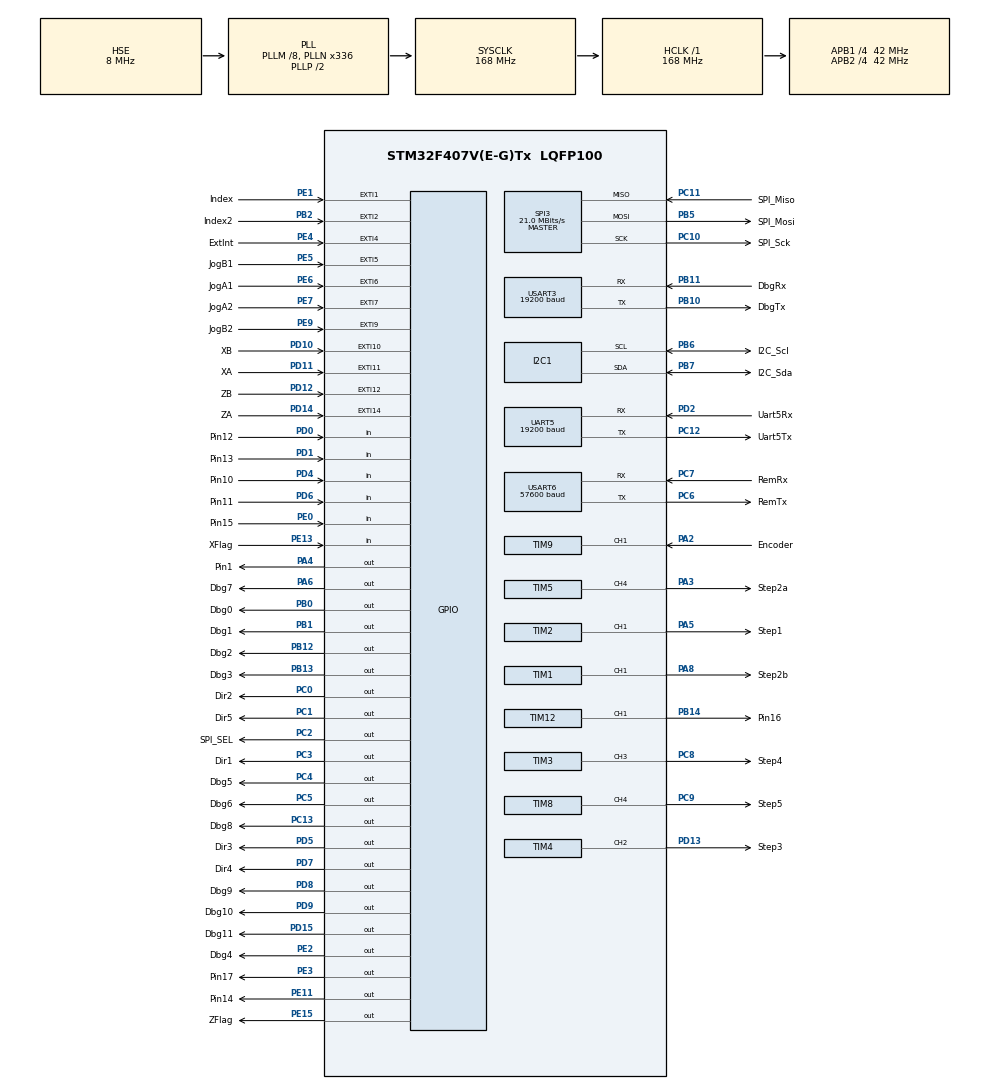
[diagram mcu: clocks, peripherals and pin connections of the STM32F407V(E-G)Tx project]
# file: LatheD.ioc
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Mcu.Family=STM32F4
Mcu.Name=STM32F407V(E-G)Tx
Mcu.Package=LQFP100
NVIC.EXTI15_10_IRQn=true\:5\:0\:true\:false\:false\:true\:false
NVIC.EXTI2_IRQn=true\:5\:0\:true\:false\:false\:true\:false
NVIC.EXTI4_IRQn=true\:5\:0\:true\:false\:false\:true\:false
NVIC.EXTI9_5_IRQn=true\:5\:0\:true\:false\:false\:true\:false
NVIC.PriorityGroup=NVIC_PRIORITYGROUP_4
NVIC.TIM1_BRK_TIM9_IRQn=true\:6\:0\:true\:false\:false\:true\:false
NVIC.TIM1_TRG_COM_TIM11_IRQn=true\:6\:0\:true\:false\:false\:true\:false
NVIC.TIM1_UP_TIM10_IRQn=true\:4\:0\:true\:false\:false\:true\:false
NVIC.TIM2_IRQn=true\:3\:0\:true\:false\:false\:true\:false
NVIC.TIM3_IRQn=true\:2\:0\:true\:false\:false\:true\:false
NVIC.TIM4_IRQn=true\:4\:0\:true\:false\:false\:true\:false
NVIC.TIM5_IRQn=true\:2\:0\:true\:false\:false\:true\:false
NVIC.TIM7_IRQn=true\:5\:0\:true\:false\:false\:true\:false
NVIC.TIM8_BRK_TIM12_IRQn=true\:5\:0\:true\:false\:false\:true\:false
NVIC.TIM8_TRG_COM_TIM14_IRQn=true\:0\:0\:false\:false\:false\:true\:false
NVIC.TIM8_UP_TIM13_IRQn=true\:5\:0\:true\:false\:false\:true\:false
NVIC.USART6_IRQn=true\:6\:0\:true\:false\:false\:true\:false
PA13.Mode=JTAG_5_pins
PA13.Signal=SYS_JTMS-SWDIO
PA14.Mode=JTAG_5_pins
PA14.Signal=SYS_JTCK-SWCLK
PA15.Mode=JTAG_5_pins
PA15.Signal=SYS_JTDI
PA2.GPIO_Label=Encoder
PA2.Signal=S_TIM9_CH1
PA3.GPIO_Label=Step2a
PA3.Signal=S_TIM5_CH4
PA4.GPIO_Label=Pin1
PA4.Signal=GPIO_Output
PA5.GPIO_Label=Step1
PA5.Signal=S_TIM2_CH1_ETR
PA6.GPIO_Label=Dbg7
PA6.Signal=GPIO_Output
PA8.GPIO_Label=Step2b
PA8.Signal=S_TIM1_CH1
PB0.GPIO_Label=Dbg0
PB0.Signal=GPIO_Output
PB1.GPIO_Label=Dbg1
PB1.Signal=GPIO_Output
PB10.GPIO_Label=DbgTx
PB10.Mode=Asynchronous
PB10.Signal=USART3_TX
PB11.GPIO_Label=DbgRx
PB11.Mode=Asynchronous
PB11.Signal=USART3_RX
PB12.GPIO_Label=Dbg2
PB12.Signal=GPIO_Output
PB13.GPIO_Label=Dbg3
PB13.Signal=GPIO_Output
PB14.GPIO_Label=Pin16
PB14.Signal=S_TIM12_CH1
PB2.GPIO_Label=Index2
PB2.Signal=GPXTI2
PB3.Mode=JTAG_5_pins
PB3.Signal=SYS_JTDO-SWO
PB4.Mode=JTAG_5_pins
PB4.Signal=SYS_JTRST
PB5.GPIO_Label=SPI_Mosi
PB5.Mode=Full_Duplex_Master
PB5.Signal=SPI3_MOSI
PB6.GPIO_Label=I2C_Scl
PB6.Mode=I2C
PB6.Signal=I2C1_SCL
PB7.GPIO_Label=I2C_Sda
PB7.Mode=I2C
PB7.Signal=I2C1_SDA
PC0.GPIO_Label=Dir2
PC0.Signal=GPIO_Output
PC1.GPIO_Label=Dir5
PC1.Signal=GPIO_Output
PC10.GPIO_Label=SPI_Sck
PC10.Mode=Full_Duplex_Master
PC10.Signal=SPI3_SCK
PC11.GPIO_Label=SPI_Miso
PC11.Mode=Full_Duplex_Master
PC11.Signal=SPI3_MISO
PC12.GPIO_Label=Uart5Tx
PC12.Mode=Asynchronous
PC12.Signal=UART5_TX
PC13-ANTI_TAMP.GPIO_Label=Dbg8
PC13-ANTI_TAMP.Signal=GPIO_Output
PC2.GPIO_Label=SPI_SEL
PC2.Signal=GPIO_Output
PC3.GPIO_Label=Dir1
PC3.Signal=GPIO_Output
PC4.GPIO_Label=Dbg5
PC4.Signal=GPIO_Output
PC5.GPIO_Label=Dbg6
PC5.Signal=GPIO_Output
PC6.GPIO_Label=RemTx
PC6.Mode=Asynchronous
PC6.Signal=USART6_TX
PC7.GPIO_Label=RemRx
PC7.Mode=Asynchronous
PC7.Signal=USART6_RX
PC8.GPIO_Label=Step4
PC8.Signal=S_TIM3_CH3
PC9.GPIO_Label=Step5
PC9.GPIO_Speed=GPIO_SPEED_FREQ_LOW
PC9.Signal=S_TIM8_CH4
PD0.GPIO_Label=Pin12
PD0.Signal=GPIO_Input
PD1.GPIO_Label=Pin13
PD1.Signal=GPIO_Input
PD10.GPIO_Label=XB
PD10.GPIO_ModeDefaultEXTI=GPIO_MODE_IT_RISING_FALLING
PD10.Signal=GPXTI10
PD11.GPIO_Label=XA
PD11.GPIO_ModeDefaultEXTI=GPIO_MODE_IT_RISING_FALLING
PD11.Signal=GPXTI11
PD12.GPIO_Label=ZB
PD12.GPIO_ModeDefaultEXTI=GPIO_MODE_IT_RISING_FALLING
PD12.Signal=GPXTI12
PD13.GPIO_Label=Step3
PD13.Signal=S_TIM4_CH2
PD14.GPIO_Label=ZA
PD14.GPIO_ModeDefaultEXTI=GPIO_MODE_IT_RISING_FALLING
PD14.Signal=GPXTI14
PD15.GPIO_Label=Dbg11
PD15.Signal=GPIO_Output
PD2.GPIO_Label=Uart5Rx
PD2.Mode=Asynchronous
PD2.Signal=UART5_RX
PD4.GPIO_Label=Pin10
PD4.Signal=GPIO_Input
PD5.GPIO_Label=Dir3
PD5.Signal=GPIO_Output
PD6.GPIO_Label=Pin11
PD6.Signal=GPIO_Input
PD7.GPIO_Label=Dir4
PD7.Signal=GPIO_Output
PD8.GPIO_Label=Dbg9
PD8.Signal=GPIO_Output
PD9.GPIO_Label=Dbg10
PD9.Signal=GPIO_Output
PE0.GPIO_Label=Pin15
PE0.Signal=GPIO_Input
PE1.GPIO_Label=Index
PE1.Signal=GPXTI1
PE11.GPIO_Label=Pin14
PE11.Signal=GPIO_Output
PE13.GPIO_Label=XFlag
PE13.Signal=GPIO_Input
PE15.GPIO_Label=ZFlag
PE15.Signal=GPIO_Output
PE2.GPIO_Label=Dbg4
PE2.Signal=GPIO_Output
PE3.GPIO_Label=Pin17
PE3.Signal=GPIO_Output
PE4.GPIO_Label=ExtInt
PE4.Signal=GPXTI4
PE5.GPIO_Label=JogB1
PE5.GPIO_ModeDefaultEXTI=GPIO_MODE_IT_RISING_FALLING
PE5.Signal=GPXTI5
PE6.GPIO_Label=JogA1
PE6.GPIO_ModeDefaultEXTI=GPIO_MODE_IT_RISING_FALLING
PE6.Signal=GPXTI6
PE7.GPIO_Label=JogA2
PE7.GPIO_ModeDefaultEXTI=GPIO_MODE_IT_RISING_FALLING
PE7.Signal=GPXTI7
PE9.GPIO_Label=JogB2
PE9.GPIO_ModeDefaultEXTI=GPIO_MODE_IT_RISING_FALLING
PE9.Signal=GPXTI9
PH0-OSC_IN.Mode=HSE-External-Oscillator
PH0-OSC_IN.Signal=RCC_OSC_IN
PH1-OSC_OUT.Mode=HSE-External-Oscillator
PH1-OSC_OUT.Signal=RCC_OSC_OUT
ProjectManager.HeapSize=0x400
ProjectManager.StackSize=0x200
ProjectManager.TargetToolchain=Other Toolchains (GPDSC)
RCC.48MHZClocksFreq_Value=48000000
RCC.AHBFreq_Value=168000000
RCC.APB1CLKDivider=RCC_HCLK_DIV4
RCC.APB1Freq_Value=42000000
RCC.APB1TimFreq_Value=84000000
RCC.APB2CLKDivider=RCC_HCLK_DIV4
RCC.APB2Freq_Value=42000000
RCC.APB2TimFreq_Value=84000000
RCC.CortexFreq_Value=168000000
RCC.HCLKFreq_Value=168000000
RCC.HSE_VALUE=8000000
RCC.HSI_VALUE=16000000
RCC.LSE_VALUE=32768
RCC.PLLM=8
RCC.PLLN=336
RCC.PLLQ=7
RCC.PLLSourceVirtual=RCC_PLLSOURCE_HSE
RCC.SYSCLKFreq_VALUE=168000000
RCC.SYSCLKSource=RCC_SYSCLKSOURCE_PLLCLK
RCC.VCOOutputFreq_Value=336000000
SH.S_TIM12_CH1.0=TIM12_CH1,PWM Generation1 CH1
SH.S_TIM1_CH1.0=TIM1_CH1,PWM Generation1 CH1
SH.S_TIM2_CH1_ETR.0=TIM2_CH1,PWM Generation1 CH1
SH.S_TIM3_CH3.0=TIM3_CH3,PWM Generation3 CH3
SH.S_TIM4_CH2.0=TIM4_CH2,PWM Generation2 CH2
SH.S_TIM5_CH4.0=TIM5_CH4,PWM Generation4 CH4
SH.S_TIM8_CH4.0=TIM8_CH4,PWM Generation4 CH4
SH.S_TIM9_CH1.0=TIM9_CH1,Input_Capture1_from_TI1
SPI3.CalculateBaudRate=21.0 MBits/s
SPI3.Direction=SPI_DIRECTION_2LINES
SPI3.Mode=SPI_MODE_MASTER
SPI3.VirtualType=VM_MASTER
TIM1.Channel-PWM\ Generation1\ CH1=TIM_CHANNEL_1
TIM1.CounterMode=TIM_COUNTERMODE_DOWN
TIM1.Period=65535
TIM1.Prescaler=0
TIM1.Pulse-PWM\ Generation1\ CH1=100
TIM10.Period=65535
TIM10.Prescaler=2560
TIM11.Period=10000
TIM12.Channel-PWM\ Generation1\ CH1=TIM_CHANNEL_1
TIM2.Channel-PWM\ Generation1\ CH1=TIM_CHANNEL_1
TIM2.CounterMode=TIM_COUNTERMODE_DOWN
TIM2.Period=100000
TIM2.Prescaler=0
TIM3.Channel-PWM\ Generation3\ CH3=TIM_CHANNEL_3
TIM3.CounterMode=TIM_COUNTERMODE_DOWN
TIM3.Period=10000
TIM3.TIM_MasterOutputTrigger=TIM_TRGO_UPDATE
TIM3.TIM_MasterSlaveMode=TIM_MASTERSLAVEMODE_ENABLE
TIM4.Channel-PWM\ Generation2\ CH2=TIM_CHANNEL_2
TIM4.CounterMode=TIM_COUNTERMODE_DOWN
TIM4.Period=9999
TIM4.TIM_MasterOutputTrigger=TIM_TRGO_UPDATE
TIM4.TIM_MasterSlaveMode=TIM_MASTERSLAVEMODE_DISABLE
TIM5.Channel-PWM\ Generation4\ CH4=TIM_CHANNEL_4
TIM5.CounterMode=TIM_COUNTERMODE_DOWN
TIM5.Period=100000
TIM5.Prescaler=0
TIM7.Period=10000
TIM8.Channel-PWM\ Generation4\ CH4=TIM_CHANNEL_4
TIM8.CounterMode=TIM_COUNTERMODE_DOWN
TIM8.Period=1000
TIM8.Prescaler=0
TIM8.Pulse-PWM\ Generation4\ CH4=100
TIM8.TIM_MasterOutputTrigger=TIM_TRGO_UPDATE
TIM8.TIM_MasterSlaveMode=TIM_MASTERSLAVEMODE_ENABLE
TIM9.Channel-Input_Capture1_from_TI1=TIM_CHANNEL_1
UART5.BaudRate=19200
UART5.VirtualMode=Asynchronous
USART3.BaudRate=19200
USART3.VirtualMode=VM_ASYNC
USART6.BaudRate=57600
USART6.VirtualMode=VM_ASYNC
VP_IWDG_VS_IWDG.Mode=IWDG_Activate
VP_TIM10_VS_ClockSourceINT.Mode=Enable_Timer
VP_TIM11_VS_ClockSourceINT.Mode=Enable_Timer
VP_TIM12_VS_ClockSourceINT.Mode=Internal
VP_TIM13_VS_ClockSourceINT.Mode=Enable_Timer
VP_TIM14_VS_ClockSourceINT.Mode=Enable_Timer
VP_TIM1_VS_ClockSourceINT.Mode=Internal
VP_TIM2_VS_ClockSourceINT.Mode=Internal
VP_TIM3_VS_ClockSourceINT.Mode=Internal
VP_TIM4_VS_ClockSourceINT.Mode=Internal
VP_TIM4_VS_ClockSourceITR.Mode=TriggerSource_ITR2
VP_TIM4_VS_ControllerModeTrigger.Mode=Trigger Mode
VP_TIM5_VS_ClockSourceINT.Mode=Internal
VP_TIM6_VS_ClockSourceINT.Mode=Enable_Timer
VP_TIM7_VS_ClockSourceINT.Mode=Enable_Timer
VP_TIM8_VS_ClockSourceINT.Mode=Internal
board=LatheD

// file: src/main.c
/* USER CODE BEGIN Header */
/**
  ******************************************************************************
  * @file           : main.c
  * @brief          : Main program body
  ******************************************************************************
  ** This notice applies to any and all portions of this file
  * that are not between comment pairs USER CODE BEGIN and
  * USER CODE END. Other portions of this file, whether
  * inserted by the user or by software development tools
  * are owned by their respective copyright owners.
  *
  * COPYRIGHT(c) 2018 STMicroelectronics
  *
  * Redistribution and use in source and binary forms, with or without modification,
  * are permitted provided that the following conditions are met:
  *   1. Redistributions of source code must retain the above copyright notice,
  *      this list of conditions and the following disclaimer.
  *   2. Redistributions in binary form must reproduce the above copyright notice,
  *      this list of conditions and the following disclaimer in the documentation
  *      and/or other materials provided with the distribution.
  *   3. Neither the name of STMicroelectronics nor the names of its contributors
  *      may be used to endorse or promote products derived from this software
  *      without specific prior written permission.
  *
  * THIS SOFTWARE IS PROVIDED BY THE COPYRIGHT HOLDERS AND CONTRIBUTORS "AS IS"
  * AND ANY EXPRESS OR IMPLIED WARRANTIES, INCLUDING, BUT NOT LIMITED TO, THE
  * IMPLIED WARRANTIES OF MERCHANTABILITY AND FITNESS FOR A PARTICULAR PURPOSE ARE
  * DISCLAIMED. IN NO EVENT SHALL THE COPYRIGHT HOLDER OR CONTRIBUTORS BE LIABLE
  * FOR ANY DIRECT, INDIRECT, INCIDENTAL, SPECIAL, EXEMPLARY, OR CONSEQUENTIAL
  * DAMAGES (INCLUDING, BUT NOT LIMITED TO, PROCUREMENT OF SUBSTITUTE GOODS OR
  * SERVICES; LOSS OF USE, DATA, OR PROFITS; OR BUSINESS INTERRUPTION) HOWEVER
  * CAUSED AND ON ANY THEORY OF LIABILITY, WHETHER IN CONTRACT, STRICT LIABILITY,
  * OR TORT (INCLUDING NEGLIGENCE OR OTHERWISE) ARISING IN ANY WAY OUT OF THE USE
  * OF THIS SOFTWARE, EVEN IF ADVISED OF THE POSSIBILITY OF SUCH DAMAGE.
  *
  ******************************************************************************
  */
#include "stm32f4xx_hal.h"
void HAL_TIM_MspPostInit(TIM_HandleTypeDef *htim);
/* USER CODE END Header */

#include "main.h"

/* USER CODE BEGIN Includes */

#include "sys/types.h"

/* USER CODE END Includes */

I2C_HandleTypeDef hi2c1;

IWDG_HandleTypeDef hiwdg;

SPI_HandleTypeDef hspi3;

TIM_HandleTypeDef htim1;
TIM_HandleTypeDef htim2;
TIM_HandleTypeDef htim3;
TIM_HandleTypeDef htim4;
TIM_HandleTypeDef htim5;
TIM_HandleTypeDef htim6;
TIM_HandleTypeDef htim7;
TIM_HandleTypeDef htim8;
TIM_HandleTypeDef htim9;
TIM_HandleTypeDef htim10;
TIM_HandleTypeDef htim11;
TIM_HandleTypeDef htim12;
TIM_HandleTypeDef htim13;
TIM_HandleTypeDef htim14;

UART_HandleTypeDef huart5;
UART_HandleTypeDef huart3;
UART_HandleTypeDef huart6;

/* USER CODE BEGIN PV */
/* Private variables ---------------------------------------------------------*/

/* USER CODE END PV */

void SystemClock_Config(void);
static void MX_GPIO_Init(void);
static void MX_TIM1_Init(void);
static void MX_TIM2_Init(void);
static void MX_TIM3_Init(void);
static void MX_TIM4_Init(void);
static void MX_TIM5_Init(void);
static void MX_TIM8_Init(void);
static void MX_TIM12_Init(void);
static void MX_UART5_Init(void);
static void MX_TIM7_Init(void);
static void MX_TIM14_Init(void);
static void MX_TIM11_Init(void);
static void MX_TIM10_Init(void);
static void MX_SPI3_Init(void);
static void MX_TIM6_Init(void);
static void MX_USB_OTG_FS_USB_Init(void);
static void MX_TIM13_Init(void);
static void MX_I2C1_Init(void);
static void MX_USART3_UART_Init(void);
static void MX_USART6_UART_Init(void);
static void MX_TIM9_Init(void);
static void MX_IWDG_Init(void);
/* USER CODE BEGIN PFP */
void mainLoop();

/* USER CODE END PFP */

int main(void)
{

  /* MCU Configuration--------------------------------------------------------*/

  /* Reset of all peripherals, Initializes the Flash interface and the Systick. */
  HAL_Init();

  /* Configure the system clock */
  SystemClock_Config();

  /* Initialize all configured peripherals */
  MX_GPIO_Init();
  MX_TIM1_Init();
  MX_TIM2_Init();
  MX_TIM3_Init();
  MX_TIM4_Init();
  MX_TIM5_Init();
  MX_TIM8_Init();
  MX_TIM12_Init();
  MX_UART5_Init();
  MX_TIM7_Init();
  MX_TIM14_Init();
  MX_TIM11_Init();
  MX_TIM10_Init();
  MX_SPI3_Init();
  MX_TIM6_Init();
  MX_USB_OTG_FS_USB_Init();
  MX_TIM13_Init();
  MX_I2C1_Init();
  MX_USART3_UART_Init();
  MX_USART6_UART_Init();
  MX_TIM9_Init();
  MX_IWDG_Init();
  /* USER CODE BEGIN 2 */

  mainLoop();

  /* USER CODE END 2 */

  /* Infinite loop */
  while (1)
  {

  }
}

void SystemClock_Config(void)
{
  RCC_OscInitTypeDef RCC_OscInitStruct = {0};
  RCC_ClkInitTypeDef RCC_ClkInitStruct = {0};

  /** Configure the main internal regulator output voltage
  */
  __HAL_RCC_PWR_CLK_ENABLE();
  __HAL_PWR_VOLTAGESCALING_CONFIG(PWR_REGULATOR_VOLTAGE_SCALE1);
  /** Initializes the CPU, AHB and APB busses clocks
  */
  RCC_OscInitStruct.OscillatorType = RCC_OSCILLATORTYPE_LSI|RCC_OSCILLATORTYPE_HSE;
  RCC_OscInitStruct.HSEState = RCC_HSE_ON;
  RCC_OscInitStruct.LSIState = RCC_LSI_ON;
  RCC_OscInitStruct.PLL.PLLState = RCC_PLL_ON;
  RCC_OscInitStruct.PLL.PLLSource = RCC_PLLSOURCE_HSE;
  RCC_OscInitStruct.PLL.PLLM = 8;
  RCC_OscInitStruct.PLL.PLLN = 336;
  RCC_OscInitStruct.PLL.PLLP = RCC_PLLP_DIV2;
  RCC_OscInitStruct.PLL.PLLQ = 7;
  if (HAL_RCC_OscConfig(&RCC_OscInitStruct) != HAL_OK)
  {
    Error_Handler();
  }
  /** Initializes the CPU, AHB and APB busses clocks
  */
  RCC_ClkInitStruct.ClockType = RCC_CLOCKTYPE_HCLK|RCC_CLOCKTYPE_SYSCLK
                              |RCC_CLOCKTYPE_PCLK1|RCC_CLOCKTYPE_PCLK2;
  RCC_ClkInitStruct.SYSCLKSource = RCC_SYSCLKSOURCE_PLLCLK;
  RCC_ClkInitStruct.AHBCLKDivider = RCC_SYSCLK_DIV1;
  RCC_ClkInitStruct.APB1CLKDivider = RCC_HCLK_DIV4;
  RCC_ClkInitStruct.APB2CLKDivider = RCC_HCLK_DIV4;

  if (HAL_RCC_ClockConfig(&RCC_ClkInitStruct, FLASH_LATENCY_5) != HAL_OK)
  {
    Error_Handler();
  }
}

static void MX_I2C1_Init(void)
{

  hi2c1.Instance = I2C1;
  hi2c1.Init.ClockSpeed = 100000;
  hi2c1.Init.DutyCycle = I2C_DUTYCYCLE_2;
  hi2c1.Init.OwnAddress1 = 0;
  hi2c1.Init.AddressingMode = I2C_ADDRESSINGMODE_7BIT;
  hi2c1.Init.DualAddressMode = I2C_DUALADDRESS_DISABLE;
  hi2c1.Init.OwnAddress2 = 0;
  hi2c1.Init.GeneralCallMode = I2C_GENERALCALL_DISABLE;
  hi2c1.Init.NoStretchMode = I2C_NOSTRETCH_DISABLE;
  if (HAL_I2C_Init(&hi2c1) != HAL_OK)
  {
    Error_Handler();
  }

}

static void MX_IWDG_Init(void)
{

  hiwdg.Instance = IWDG;
  hiwdg.Init.Prescaler = IWDG_PRESCALER_4;
  hiwdg.Init.Reload = 4095;
  if (HAL_IWDG_Init(&hiwdg) != HAL_OK)
  {
    Error_Handler();
  }

}

static void MX_SPI3_Init(void)
{

  /* SPI3 parameter configuration*/
  hspi3.Instance = SPI3;
  hspi3.Init.Mode = SPI_MODE_MASTER;
  hspi3.Init.Direction = SPI_DIRECTION_2LINES;
  hspi3.Init.DataSize = SPI_DATASIZE_8BIT;
  hspi3.Init.CLKPolarity = SPI_POLARITY_LOW;
  hspi3.Init.CLKPhase = SPI_PHASE_1EDGE;
  hspi3.Init.NSS = SPI_NSS_SOFT;
  hspi3.Init.BaudRatePrescaler = SPI_BAUDRATEPRESCALER_2;
  hspi3.Init.FirstBit = SPI_FIRSTBIT_MSB;
  hspi3.Init.TIMode = SPI_TIMODE_DISABLE;
  hspi3.Init.CRCCalculation = SPI_CRCCALCULATION_DISABLE;
  hspi3.Init.CRCPolynomial = 10;
  if (HAL_SPI_Init(&hspi3) != HAL_OK)
  {
    Error_Handler();
  }

}

static void MX_TIM1_Init(void)
{

  TIM_ClockConfigTypeDef sClockSourceConfig = {0};
  TIM_MasterConfigTypeDef sMasterConfig = {0};
  TIM_OC_InitTypeDef sConfigOC = {0};
  TIM_BreakDeadTimeConfigTypeDef sBreakDeadTimeConfig = {0};

  htim1.Instance = TIM1;
  htim1.Init.Prescaler = 0;
  htim1.Init.CounterMode = TIM_COUNTERMODE_DOWN;
  htim1.Init.Period = 65535;
  htim1.Init.ClockDivision = TIM_CLOCKDIVISION_DIV1;
  htim1.Init.RepetitionCounter = 0;
  htim1.Init.AutoReloadPreload = TIM_AUTORELOAD_PRELOAD_DISABLE;
  if (HAL_TIM_Base_Init(&htim1) != HAL_OK)
  {
    Error_Handler();
  }
  sClockSourceConfig.ClockSource = TIM_CLOCKSOURCE_INTERNAL;
  if (HAL_TIM_ConfigClockSource(&htim1, &sClockSourceConfig) != HAL_OK)
  {
    Error_Handler();
  }
  if (HAL_TIM_PWM_Init(&htim1) != HAL_OK)
  {
    Error_Handler();
  }
  sMasterConfig.MasterOutputTrigger = TIM_TRGO_RESET;
  sMasterConfig.MasterSlaveMode = TIM_MASTERSLAVEMODE_DISABLE;
  if (HAL_TIMEx_MasterConfigSynchronization(&htim1, &sMasterConfig) != HAL_OK)
  {
    Error_Handler();
  }
  sConfigOC.OCMode = TIM_OCMODE_PWM1;
  sConfigOC.Pulse = 100;
  sConfigOC.OCPolarity = TIM_OCPOLARITY_HIGH;
  sConfigOC.OCNPolarity = TIM_OCNPOLARITY_HIGH;
  sConfigOC.OCFastMode = TIM_OCFAST_DISABLE;
  sConfigOC.OCIdleState = TIM_OCIDLESTATE_RESET;
  sConfigOC.OCNIdleState = TIM_OCNIDLESTATE_RESET;
  if (HAL_TIM_PWM_ConfigChannel(&htim1, &sConfigOC, TIM_CHANNEL_1) != HAL_OK)
  {
    Error_Handler();
  }
  sBreakDeadTimeConfig.OffStateRunMode = TIM_OSSR_DISABLE;
  sBreakDeadTimeConfig.OffStateIDLEMode = TIM_OSSI_DISABLE;
  sBreakDeadTimeConfig.LockLevel = TIM_LOCKLEVEL_OFF;
  sBreakDeadTimeConfig.DeadTime = 0;
  sBreakDeadTimeConfig.BreakState = TIM_BREAK_DISABLE;
  sBreakDeadTimeConfig.BreakPolarity = TIM_BREAKPOLARITY_HIGH;
  sBreakDeadTimeConfig.AutomaticOutput = TIM_AUTOMATICOUTPUT_DISABLE;
  if (HAL_TIMEx_ConfigBreakDeadTime(&htim1, &sBreakDeadTimeConfig) != HAL_OK)
  {
    Error_Handler();
  }
  HAL_TIM_MspPostInit(&htim1);

}

static void MX_TIM2_Init(void)
{

  TIM_ClockConfigTypeDef sClockSourceConfig = {0};
  TIM_MasterConfigTypeDef sMasterConfig = {0};
  TIM_OC_InitTypeDef sConfigOC = {0};

  htim2.Instance = TIM2;
  htim2.Init.Prescaler = 0;
  htim2.Init.CounterMode = TIM_COUNTERMODE_DOWN;
  htim2.Init.Period = 100000;
  htim2.Init.ClockDivision = TIM_CLOCKDIVISION_DIV1;
  htim2.Init.AutoReloadPreload = TIM_AUTORELOAD_PRELOAD_DISABLE;
  if (HAL_TIM_Base_Init(&htim2) != HAL_OK)
  {
    Error_Handler();
  }
  sClockSourceConfig.ClockSource = TIM_CLOCKSOURCE_INTERNAL;
  if (HAL_TIM_ConfigClockSource(&htim2, &sClockSourceConfig) != HAL_OK)
  {
    Error_Handler();
  }
  if (HAL_TIM_PWM_Init(&htim2) != HAL_OK)
  {
    Error_Handler();
  }
  sMasterConfig.MasterOutputTrigger = TIM_TRGO_RESET;
  sMasterConfig.MasterSlaveMode = TIM_MASTERSLAVEMODE_DISABLE;
  if (HAL_TIMEx_MasterConfigSynchronization(&htim2, &sMasterConfig) != HAL_OK)
  {
    Error_Handler();
  }
  sConfigOC.OCMode = TIM_OCMODE_PWM1;
  sConfigOC.Pulse = 0;
  sConfigOC.OCPolarity = TIM_OCPOLARITY_LOW;
  sConfigOC.OCFastMode = TIM_OCFAST_DISABLE;
  if (HAL_TIM_PWM_ConfigChannel(&htim2, &sConfigOC, TIM_CHANNEL_1) != HAL_OK)
  {
    Error_Handler();
  }
  HAL_TIM_MspPostInit(&htim2);

}

static void MX_TIM3_Init(void)
{

  TIM_ClockConfigTypeDef sClockSourceConfig = {0};
  TIM_MasterConfigTypeDef sMasterConfig = {0};
  TIM_OC_InitTypeDef sConfigOC = {0};

  htim3.Instance = TIM3;
  htim3.Init.Prescaler = 0;
  htim3.Init.CounterMode = TIM_COUNTERMODE_DOWN;
  htim3.Init.Period = 10000;
  htim3.Init.ClockDivision = TIM_CLOCKDIVISION_DIV1;
  htim3.Init.AutoReloadPreload = TIM_AUTORELOAD_PRELOAD_DISABLE;
  if (HAL_TIM_Base_Init(&htim3) != HAL_OK)
  {
    Error_Handler();
  }
  sClockSourceConfig.ClockSource = TIM_CLOCKSOURCE_INTERNAL;
  if (HAL_TIM_ConfigClockSource(&htim3, &sClockSourceConfig) != HAL_OK)
  {
    Error_Handler();
  }
  if (HAL_TIM_PWM_Init(&htim3) != HAL_OK)
  {
    Error_Handler();
  }
  sMasterConfig.MasterOutputTrigger = TIM_TRGO_UPDATE;
  sMasterConfig.MasterSlaveMode = TIM_MASTERSLAVEMODE_ENABLE;
  if (HAL_TIMEx_MasterConfigSynchronization(&htim3, &sMasterConfig) != HAL_OK)
  {
    Error_Handler();
  }
  sConfigOC.OCMode = TIM_OCMODE_PWM1;
  sConfigOC.Pulse = 0;
  sConfigOC.OCPolarity = TIM_OCPOLARITY_HIGH;
  sConfigOC.OCFastMode = TIM_OCFAST_DISABLE;
  if (HAL_TIM_PWM_ConfigChannel(&htim3, &sConfigOC, TIM_CHANNEL_3) != HAL_OK)
  {
    Error_Handler();
  }
  HAL_TIM_MspPostInit(&htim3);

}

static void MX_TIM4_Init(void)
{

  TIM_ClockConfigTypeDef sClockSourceConfig = {0};
  TIM_SlaveConfigTypeDef sSlaveConfig = {0};
  TIM_MasterConfigTypeDef sMasterConfig = {0};
  TIM_OC_InitTypeDef sConfigOC = {0};

  htim4.Instance = TIM4;
  htim4.Init.Prescaler = 0;
  htim4.Init.CounterMode = TIM_COUNTERMODE_DOWN;
  htim4.Init.Period = 9999;
  htim4.Init.ClockDivision = TIM_CLOCKDIVISION_DIV1;
  htim4.Init.AutoReloadPreload = TIM_AUTORELOAD_PRELOAD_DISABLE;
  if (HAL_TIM_Base_Init(&htim4) != HAL_OK)
  {
    Error_Handler();
  }
  sClockSourceConfig.ClockSource = TIM_CLOCKSOURCE_INTERNAL;
  if (HAL_TIM_ConfigClockSource(&htim4, &sClockSourceConfig) != HAL_OK)
  {
    Error_Handler();
  }
  if (HAL_TIM_PWM_Init(&htim4) != HAL_OK)
  {
    Error_Handler();
  }
  sSlaveConfig.SlaveMode = TIM_SLAVEMODE_TRIGGER;
  sSlaveConfig.InputTrigger = TIM_TS_ITR2;
  if (HAL_TIM_SlaveConfigSynchro(&htim4, &sSlaveConfig) != HAL_OK)
  {
    Error_Handler();
  }
  sMasterConfig.MasterOutputTrigger = TIM_TRGO_UPDATE;
  sMasterConfig.MasterSlaveMode = TIM_MASTERSLAVEMODE_DISABLE;
  if (HAL_TIMEx_MasterConfigSynchronization(&htim4, &sMasterConfig) != HAL_OK)
  {
    Error_Handler();
  }
  sConfigOC.OCMode = TIM_OCMODE_PWM1;
  sConfigOC.Pulse = 0;
  sConfigOC.OCPolarity = TIM_OCPOLARITY_HIGH;
  sConfigOC.OCFastMode = TIM_OCFAST_DISABLE;
  if (HAL_TIM_PWM_ConfigChannel(&htim4, &sConfigOC, TIM_CHANNEL_2) != HAL_OK)
  {
    Error_Handler();
  }
  HAL_TIM_MspPostInit(&htim4);

}

static void MX_TIM5_Init(void)
{

  TIM_ClockConfigTypeDef sClockSourceConfig = {0};
  TIM_MasterConfigTypeDef sMasterConfig = {0};
  TIM_OC_InitTypeDef sConfigOC = {0};

  htim5.Instance = TIM5;
  htim5.Init.Prescaler = 0;
  htim5.Init.CounterMode = TIM_COUNTERMODE_DOWN;
  htim5.Init.Period = 100000;
  htim5.Init.ClockDivision = TIM_CLOCKDIVISION_DIV1;
  htim5.Init.AutoReloadPreload = TIM_AUTORELOAD_PRELOAD_DISABLE;
  if (HAL_TIM_Base_Init(&htim5) != HAL_OK)
  {
    Error_Handler();
  }
  sClockSourceConfig.ClockSource = TIM_CLOCKSOURCE_INTERNAL;
  if (HAL_TIM_ConfigClockSource(&htim5, &sClockSourceConfig) != HAL_OK)
  {
    Error_Handler();
  }
  if (HAL_TIM_PWM_Init(&htim5) != HAL_OK)
  {
    Error_Handler();
  }
  sMasterConfig.MasterOutputTrigger = TIM_TRGO_RESET;
  sMasterConfig.MasterSlaveMode = TIM_MASTERSLAVEMODE_DISABLE;
  if (HAL_TIMEx_MasterConfigSynchronization(&htim5, &sMasterConfig) != HAL_OK)
  {
    Error_Handler();
  }
  sConfigOC.OCMode = TIM_OCMODE_PWM1;
  sConfigOC.Pulse = 0;
  sConfigOC.OCPolarity = TIM_OCPOLARITY_LOW;
  sConfigOC.OCFastMode = TIM_OCFAST_DISABLE;
  if (HAL_TIM_PWM_ConfigChannel(&htim5, &sConfigOC, TIM_CHANNEL_4) != HAL_OK)
  {
    Error_Handler();
  }
  HAL_TIM_MspPostInit(&htim5);

}

static void MX_TIM6_Init(void)
{

  TIM_MasterConfigTypeDef sMasterConfig = {0};

  htim6.Instance = TIM6;
  htim6.Init.Prescaler = 0;
  htim6.Init.CounterMode = TIM_COUNTERMODE_UP;
  htim6.Init.Period = 0;
  htim6.Init.AutoReloadPreload = TIM_AUTORELOAD_PRELOAD_DISABLE;
  if (HAL_TIM_Base_Init(&htim6) != HAL_OK)
  {
    Error_Handler();
  }
  sMasterConfig.MasterOutputTrigger = TIM_TRGO_RESET;
  sMasterConfig.MasterSlaveMode = TIM_MASTERSLAVEMODE_DISABLE;
  if (HAL_TIMEx_MasterConfigSynchronization(&htim6, &sMasterConfig) != HAL_OK)
  {
    Error_Handler();
  }

}

static void MX_TIM7_Init(void)
{

  TIM_MasterConfigTypeDef sMasterConfig = {0};

  htim7.Instance = TIM7;
  htim7.Init.Prescaler = 0;
  htim7.Init.CounterMode = TIM_COUNTERMODE_UP;
  htim7.Init.Period = 10000;
  htim7.Init.AutoReloadPreload = TIM_AUTORELOAD_PRELOAD_DISABLE;
  if (HAL_TIM_Base_Init(&htim7) != HAL_OK)
  {
    Error_Handler();
  }
  sMasterConfig.MasterOutputTrigger = TIM_TRGO_RESET;
  sMasterConfig.MasterSlaveMode = TIM_MASTERSLAVEMODE_DISABLE;
  if (HAL_TIMEx_MasterConfigSynchronization(&htim7, &sMasterConfig) != HAL_OK)
  {
    Error_Handler();
  }

}

static void MX_TIM8_Init(void)
{

  TIM_ClockConfigTypeDef sClockSourceConfig = {0};
  TIM_MasterConfigTypeDef sMasterConfig = {0};
  TIM_OC_InitTypeDef sConfigOC = {0};
  TIM_BreakDeadTimeConfigTypeDef sBreakDeadTimeConfig = {0};

  htim8.Instance = TIM8;
  htim8.Init.Prescaler = 0;
  htim8.Init.CounterMode = TIM_COUNTERMODE_DOWN;
  htim8.Init.Period = 1000;
  htim8.Init.ClockDivision = TIM_CLOCKDIVISION_DIV1;
  htim8.Init.RepetitionCounter = 0;
  htim8.Init.AutoReloadPreload = TIM_AUTORELOAD_PRELOAD_DISABLE;
  if (HAL_TIM_Base_Init(&htim8) != HAL_OK)
  {
    Error_Handler();
  }
  sClockSourceConfig.ClockSource = TIM_CLOCKSOURCE_INTERNAL;
  if (HAL_TIM_ConfigClockSource(&htim8, &sClockSourceConfig) != HAL_OK)
  {
    Error_Handler();
  }
  if (HAL_TIM_PWM_Init(&htim8) != HAL_OK)
  {
    Error_Handler();
  }
  sMasterConfig.MasterOutputTrigger = TIM_TRGO_UPDATE;
  sMasterConfig.MasterSlaveMode = TIM_MASTERSLAVEMODE_ENABLE;
  if (HAL_TIMEx_MasterConfigSynchronization(&htim8, &sMasterConfig) != HAL_OK)
  {
    Error_Handler();
  }
  sConfigOC.OCMode = TIM_OCMODE_PWM1;
  sConfigOC.Pulse = 100;
  sConfigOC.OCPolarity = TIM_OCPOLARITY_HIGH;
  sConfigOC.OCFastMode = TIM_OCFAST_DISABLE;
  sConfigOC.OCIdleState = TIM_OCIDLESTATE_RESET;
  sConfigOC.OCNIdleState = TIM_OCNIDLESTATE_RESET;
  if (HAL_TIM_PWM_ConfigChannel(&htim8, &sConfigOC, TIM_CHANNEL_4) != HAL_OK)
  {
    Error_Handler();
  }
  sBreakDeadTimeConfig.OffStateRunMode = TIM_OSSR_DISABLE;
  sBreakDeadTimeConfig.OffStateIDLEMode = TIM_OSSI_DISABLE;
  sBreakDeadTimeConfig.LockLevel = TIM_LOCKLEVEL_OFF;
  sBreakDeadTimeConfig.DeadTime = 0;
  sBreakDeadTimeConfig.BreakState = TIM_BREAK_DISABLE;
  sBreakDeadTimeConfig.BreakPolarity = TIM_BREAKPOLARITY_HIGH;
  sBreakDeadTimeConfig.AutomaticOutput = TIM_AUTOMATICOUTPUT_DISABLE;
  if (HAL_TIMEx_ConfigBreakDeadTime(&htim8, &sBreakDeadTimeConfig) != HAL_OK)
  {
    Error_Handler();
  }
  HAL_TIM_MspPostInit(&htim8);

}

static void MX_TIM9_Init(void)
{

  TIM_IC_InitTypeDef sConfigIC = {0};

  htim9.Instance = TIM9;
  htim9.Init.Prescaler = 0;
  htim9.Init.CounterMode = TIM_COUNTERMODE_UP;
  htim9.Init.Period = 0;
  htim9.Init.ClockDivision = TIM_CLOCKDIVISION_DIV1;
  htim9.Init.AutoReloadPreload = TIM_AUTORELOAD_PRELOAD_DISABLE;
  if (HAL_TIM_IC_Init(&htim9) != HAL_OK)
  {
    Error_Handler();
  }
  sConfigIC.ICPolarity = TIM_INPUTCHANNELPOLARITY_RISING;
  sConfigIC.ICSelection = TIM_ICSELECTION_DIRECTTI;
  sConfigIC.ICPrescaler = TIM_ICPSC_DIV1;
  sConfigIC.ICFilter = 0;
  if (HAL_TIM_IC_ConfigChannel(&htim9, &sConfigIC, TIM_CHANNEL_1) != HAL_OK)
  {
    Error_Handler();
  }

}

static void MX_TIM10_Init(void)
{

  htim10.Instance = TIM10;
  htim10.Init.Prescaler = 2560;
  htim10.Init.CounterMode = TIM_COUNTERMODE_UP;
  htim10.Init.Period = 65535;
  htim10.Init.ClockDivision = TIM_CLOCKDIVISION_DIV1;
  htim10.Init.AutoReloadPreload = TIM_AUTORELOAD_PRELOAD_DISABLE;
  if (HAL_TIM_Base_Init(&htim10) != HAL_OK)
  {
    Error_Handler();
  }

}

static void MX_TIM11_Init(void)
{

  htim11.Instance = TIM11;
  htim11.Init.Prescaler = 0;
  htim11.Init.CounterMode = TIM_COUNTERMODE_UP;
  htim11.Init.Period = 10000;
  htim11.Init.ClockDivision = TIM_CLOCKDIVISION_DIV1;
  htim11.Init.AutoReloadPreload = TIM_AUTORELOAD_PRELOAD_DISABLE;
  if (HAL_TIM_Base_Init(&htim11) != HAL_OK)
  {
    Error_Handler();
  }

}

static void MX_TIM12_Init(void)
{

  TIM_ClockConfigTypeDef sClockSourceConfig = {0};
  TIM_OC_InitTypeDef sConfigOC = {0};

  htim12.Instance = TIM12;
  htim12.Init.Prescaler = 0;
  htim12.Init.CounterMode = TIM_COUNTERMODE_UP;
  htim12.Init.Period = 0;
  htim12.Init.ClockDivision = TIM_CLOCKDIVISION_DIV1;
  htim12.Init.AutoReloadPreload = TIM_AUTORELOAD_PRELOAD_DISABLE;
  if (HAL_TIM_Base_Init(&htim12) != HAL_OK)
  {
    Error_Handler();
  }
  sClockSourceConfig.ClockSource = TIM_CLOCKSOURCE_INTERNAL;
  if (HAL_TIM_ConfigClockSource(&htim12, &sClockSourceConfig) != HAL_OK)
  {
    Error_Handler();
  }
  if (HAL_TIM_PWM_Init(&htim12) != HAL_OK)
  {
    Error_Handler();
  }
  sConfigOC.OCMode = TIM_OCMODE_PWM1;
  sConfigOC.Pulse = 0;
  sConfigOC.OCPolarity = TIM_OCPOLARITY_HIGH;
  sConfigOC.OCFastMode = TIM_OCFAST_DISABLE;
  if (HAL_TIM_PWM_ConfigChannel(&htim12, &sConfigOC, TIM_CHANNEL_1) != HAL_OK)
  {
    Error_Handler();
  }
  HAL_TIM_MspPostInit(&htim12);

}

static void MX_TIM13_Init(void)
{

  htim13.Instance = TIM13;
  htim13.Init.Prescaler = 0;
  htim13.Init.CounterMode = TIM_COUNTERMODE_UP;
  htim13.Init.Period = 0;
  htim13.Init.ClockDivision = TIM_CLOCKDIVISION_DIV1;
  htim13.Init.AutoReloadPreload = TIM_AUTORELOAD_PRELOAD_DISABLE;
  if (HAL_TIM_Base_Init(&htim13) != HAL_OK)
  {
    Error_Handler();
  }

}

static void MX_TIM14_Init(void)
{

  htim14.Instance = TIM14;
  htim14.Init.Prescaler = 0;
  htim14.Init.CounterMode = TIM_COUNTERMODE_UP;
  htim14.Init.Period = 0;
  htim14.Init.ClockDivision = TIM_CLOCKDIVISION_DIV1;
  htim14.Init.AutoReloadPreload = TIM_AUTORELOAD_PRELOAD_DISABLE;
  if (HAL_TIM_Base_Init(&htim14) != HAL_OK)
  {
    Error_Handler();
  }

}

static void MX_UART5_Init(void)
{

  huart5.Instance = UART5;
  huart5.Init.BaudRate = 19200;
  huart5.Init.WordLength = UART_WORDLENGTH_8B;
  huart5.Init.StopBits = UART_STOPBITS_1;
  huart5.Init.Parity = UART_PARITY_NONE;
  huart5.Init.Mode = UART_MODE_TX_RX;
  huart5.Init.HwFlowCtl = UART_HWCONTROL_NONE;
  huart5.Init.OverSampling = UART_OVERSAMPLING_16;
  if (HAL_UART_Init(&huart5) != HAL_OK)
  {
    Error_Handler();
  }

}

static void MX_USART3_UART_Init(void)
{

  huart3.Instance = USART3;
  huart3.Init.BaudRate = 19200;
  huart3.Init.WordLength = UART_WORDLENGTH_8B;
  huart3.Init.StopBits = UART_STOPBITS_1;
  huart3.Init.Parity = UART_PARITY_NONE;
  huart3.Init.Mode = UART_MODE_TX_RX;
  huart3.Init.HwFlowCtl = UART_HWCONTROL_NONE;
  huart3.Init.OverSampling = UART_OVERSAMPLING_16;
  if (HAL_UART_Init(&huart3) != HAL_OK)
  {
    Error_Handler();
  }

}

static void MX_USART6_UART_Init(void)
{

  huart6.Instance = USART6;
  huart6.Init.BaudRate = 57600;
  huart6.Init.WordLength = UART_WORDLENGTH_8B;
  huart6.Init.StopBits = UART_STOPBITS_1;
  huart6.Init.Parity = UART_PARITY_NONE;
  huart6.Init.Mode = UART_MODE_TX_RX;
  huart6.Init.HwFlowCtl = UART_HWCONTROL_NONE;
  huart6.Init.OverSampling = UART_OVERSAMPLING_16;
  if (HAL_UART_Init(&huart6) != HAL_OK)
  {
    Error_Handler();
  }

}

static void MX_USB_OTG_FS_USB_Init(void)
{

}

static void MX_GPIO_Init(void)
{
  GPIO_InitTypeDef GPIO_InitStruct = {0};

  /* GPIO Ports Clock Enable */
  __HAL_RCC_GPIOE_CLK_ENABLE();
  __HAL_RCC_GPIOC_CLK_ENABLE();
  __HAL_RCC_GPIOH_CLK_ENABLE();
  __HAL_RCC_GPIOA_CLK_ENABLE();
  __HAL_RCC_GPIOB_CLK_ENABLE();
  __HAL_RCC_GPIOD_CLK_ENABLE();

  /*Configure GPIO pin Output Level */
  HAL_GPIO_WritePin(GPIOE, Dbg4_Pin|Pin17_Pin|Pin14_Pin|ZFlag_Pin, GPIO_PIN_RESET);

  /*Configure GPIO pin Output Level */
  HAL_GPIO_WritePin(GPIOC, Dbg8_Pin|Dir2_Pin|Dir5_Pin|SPI_SEL_Pin
                          |Dir1_Pin|Dbg5_Pin|Dbg6_Pin, GPIO_PIN_RESET);

  /*Configure GPIO pin Output Level */
  HAL_GPIO_WritePin(GPIOA, Pin1_Pin|Dbg7_Pin, GPIO_PIN_RESET);

  /*Configure GPIO pin Output Level */
  HAL_GPIO_WritePin(GPIOB, Dbg0_Pin|Dbg1_Pin|Dbg2_Pin|Dbg3_Pin, GPIO_PIN_RESET);

  /*Configure GPIO pin Output Level */
  HAL_GPIO_WritePin(GPIOD, Dbg9_Pin|Dbg10_Pin|Dbg11_Pin|Dir3_Pin
                          |Dir4_Pin, GPIO_PIN_RESET);

  /*Configure GPIO pins : Dbg4_Pin Pin17_Pin Pin14_Pin ZFlag_Pin */
  GPIO_InitStruct.Pin = Dbg4_Pin|Pin17_Pin|Pin14_Pin|ZFlag_Pin;
  GPIO_InitStruct.Mode = GPIO_MODE_OUTPUT_PP;
  GPIO_InitStruct.Pull = GPIO_NOPULL;
  GPIO_InitStruct.Speed = GPIO_SPEED_FREQ_LOW;
  HAL_GPIO_Init(GPIOE, &GPIO_InitStruct);

  /*Configure GPIO pins : ExtInt_Pin Index_Pin */
  GPIO_InitStruct.Pin = ExtInt_Pin|Index_Pin;
  GPIO_InitStruct.Mode = GPIO_MODE_IT_RISING;
  GPIO_InitStruct.Pull = GPIO_NOPULL;
  HAL_GPIO_Init(GPIOE, &GPIO_InitStruct);

  /*Configure GPIO pins : JogB1_Pin JogA1_Pin JogA2_Pin JogB2_Pin */
  GPIO_InitStruct.Pin = JogB1_Pin|JogA1_Pin|JogA2_Pin|JogB2_Pin;
  GPIO_InitStruct.Mode = GPIO_MODE_IT_RISING_FALLING;
  GPIO_InitStruct.Pull = GPIO_NOPULL;
  HAL_GPIO_Init(GPIOE, &GPIO_InitStruct);

  /*Configure GPIO pins : Dbg8_Pin Dir2_Pin Dir5_Pin SPI_SEL_Pin
                           Dir1_Pin Dbg5_Pin Dbg6_Pin */
  GPIO_InitStruct.Pin = Dbg8_Pin|Dir2_Pin|Dir5_Pin|SPI_SEL_Pin
                          |Dir1_Pin|Dbg5_Pin|Dbg6_Pin;
  GPIO_InitStruct.Mode = GPIO_MODE_OUTPUT_PP;
  GPIO_InitStruct.Pull = GPIO_NOPULL;
  GPIO_InitStruct.Speed = GPIO_SPEED_FREQ_LOW;
  HAL_GPIO_Init(GPIOC, &GPIO_InitStruct);

  /*Configure GPIO pins : Pin1_Pin Dbg7_Pin */
  GPIO_InitStruct.Pin = Pin1_Pin|Dbg7_Pin;
  GPIO_InitStruct.Mode = GPIO_MODE_OUTPUT_PP;
  GPIO_InitStruct.Pull = GPIO_NOPULL;
  GPIO_InitStruct.Speed = GPIO_SPEED_FREQ_LOW;
  HAL_GPIO_Init(GPIOA, &GPIO_InitStruct);

  /*Configure GPIO pins : Dbg0_Pin Dbg1_Pin Dbg2_Pin Dbg3_Pin */
  GPIO_InitStruct.Pin = Dbg0_Pin|Dbg1_Pin|Dbg2_Pin|Dbg3_Pin;
  GPIO_InitStruct.Mode = GPIO_MODE_OUTPUT_PP;
  GPIO_InitStruct.Pull = GPIO_NOPULL;
  GPIO_InitStruct.Speed = GPIO_SPEED_FREQ_LOW;
  HAL_GPIO_Init(GPIOB, &GPIO_InitStruct);

  /*Configure GPIO pin : Index2_Pin */
  GPIO_InitStruct.Pin = Index2_Pin;
  GPIO_InitStruct.Mode = GPIO_MODE_IT_RISING;
  GPIO_InitStruct.Pull = GPIO_NOPULL;
  HAL_GPIO_Init(Index2_GPIO_Port, &GPIO_InitStruct);

  /*Configure GPIO pins : XFlag_Pin Pin15_Pin */
  GPIO_InitStruct.Pin = XFlag_Pin|Pin15_Pin;
  GPIO_InitStruct.Mode = GPIO_MODE_INPUT;
  GPIO_InitStruct.Pull = GPIO_NOPULL;
  HAL_GPIO_Init(GPIOE, &GPIO_InitStruct);

  /*Configure GPIO pins : Dbg9_Pin Dbg10_Pin Dbg11_Pin Dir3_Pin
                           Dir4_Pin */
  GPIO_InitStruct.Pin = Dbg9_Pin|Dbg10_Pin|Dbg11_Pin|Dir3_Pin
                          |Dir4_Pin;
  GPIO_InitStruct.Mode = GPIO_MODE_OUTPUT_PP;
  GPIO_InitStruct.Pull = GPIO_NOPULL;
  GPIO_InitStruct.Speed = GPIO_SPEED_FREQ_LOW;
  HAL_GPIO_Init(GPIOD, &GPIO_InitStruct);

  /*Configure GPIO pins : XB_Pin XA_Pin ZB_Pin ZA_Pin */
  GPIO_InitStruct.Pin = XB_Pin|XA_Pin|ZB_Pin|ZA_Pin;
  GPIO_InitStruct.Mode = GPIO_MODE_IT_RISING_FALLING;
  GPIO_InitStruct.Pull = GPIO_NOPULL;
  HAL_GPIO_Init(GPIOD, &GPIO_InitStruct);

  /*Configure GPIO pins : PA10 PA11 PA12 */
  GPIO_InitStruct.Pin = GPIO_PIN_10|GPIO_PIN_11|GPIO_PIN_12;
  GPIO_InitStruct.Mode = GPIO_MODE_AF_PP;
  GPIO_InitStruct.Pull = GPIO_NOPULL;
  GPIO_InitStruct.Speed = GPIO_SPEED_FREQ_VERY_HIGH;
  GPIO_InitStruct.Alternate = GPIO_AF10_OTG_FS;
  HAL_GPIO_Init(GPIOA, &GPIO_InitStruct);

  /*Configure GPIO pins : Pin12_Pin Pin13_Pin Pin10_Pin Pin11_Pin */
  GPIO_InitStruct.Pin = Pin12_Pin|Pin13_Pin|Pin10_Pin|Pin11_Pin;
  GPIO_InitStruct.Mode = GPIO_MODE_INPUT;
  GPIO_InitStruct.Pull = GPIO_NOPULL;
  HAL_GPIO_Init(GPIOD, &GPIO_InitStruct);

  /* EXTI interrupt init*/
  HAL_NVIC_SetPriority(EXTI2_IRQn, 5, 0);
  HAL_NVIC_EnableIRQ(EXTI2_IRQn);

  HAL_NVIC_SetPriority(EXTI4_IRQn, 5, 0);
  HAL_NVIC_EnableIRQ(EXTI4_IRQn);

  HAL_NVIC_SetPriority(EXTI9_5_IRQn, 5, 0);
  HAL_NVIC_EnableIRQ(EXTI9_5_IRQn);

  HAL_NVIC_SetPriority(EXTI15_10_IRQn, 5, 0);
  HAL_NVIC_EnableIRQ(EXTI15_10_IRQn);

}

/* USER CODE BEGIN 4 */

ssize_t _write (int fd, const char* buf, size_t nbyte);

void _init()
{
}

caddr_t _sbrk(int incr)
{
 extern char _end;		/* Defined by the linker */
 static char *heap_end;
 char *prev_heap_end;
 char *sp = (char *)&sp;

 if (heap_end == 0)
 {
  heap_end = &_end;
 }
 prev_heap_end = heap_end;
 heap_end += incr;
 if (heap_end > sp)
 {
  _write (1, "Heap and stack collision\n", 25);
//  errno = ENOMEM;
  return (caddr_t)-1;
 }
 return (caddr_t) prev_heap_end;
}

void _close()
{
}

int _fstat()
{
 return(0);
}

int _isatty()
{
 return(1);
}

void _lseek()
{
}

void _read()
{
}

/* USER CODE END 4 */

void Error_Handler(void)
{
  while(1)
  {
  }
}

/************************ (C) COPYRIGHT STMicroelectronics *****END OF FILE****/
